# Confidential Information of ARM, Inc.
# Use subject to ARM license.
# Copyright (c) 2026 ARM, Inc.

# ACI Version r0p0-00eac0

# Reifier 3.1.1

VERSION 5.6 ;

BUSBITCHARS "[]" ;

#name: sram_sp_hdc_svt_rvt_hvt Compiler|TSMC cln65gplus 65nm Process, 0.525um2 Bitcell
#version: r0p0-00eac0
#comment: 
#configuration:  -instname "picosoc_sram_2048x32" -words 2048 -bits 32 -frequency 100 -mux 16 -pipeline off -write_mask on -wp_size 8 -write_thru on -top_layer "m5-m9" -power_type otc -redundancy off -rcols 2 -rrows 2 -bmux off -ser none -back_biasing off -power_gating off -retention on -ema on -atf off -cust_comment "" -bus_notation on -left_bus_delim "[" -right_bus_delim "]" -pwr_gnd_rename "VDDPE:VDDPE,VDDCE:VDDCE,VSSE:VSSE" -prefix "" -name_case upper -check_instname off -diodes on -drive 6 -dnw off -asvm on -corners ff_1p10v_1p10v_125c,tt_1p00v_1p00v_25c,ff_1p10v_1p10v_0c,ss_0p90v_0p90v_125c,ff_1p10v_1p10v_m40c,ss_0p90v_0p90v_m40c
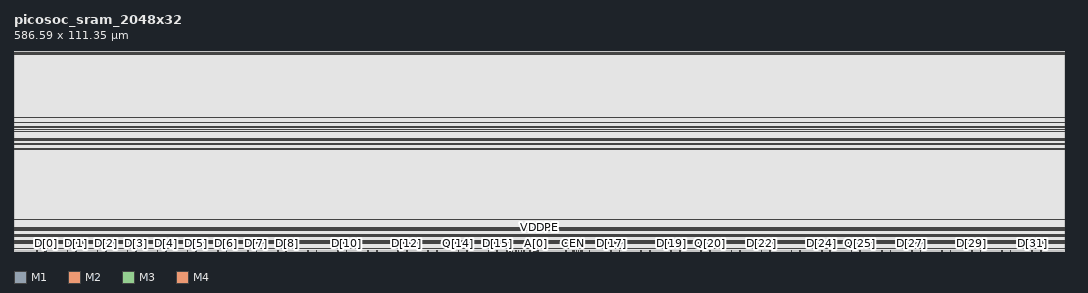
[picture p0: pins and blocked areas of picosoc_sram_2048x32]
MACRO picosoc_sram_2048x32
  FOREIGN picosoc_sram_2048x32 0 0 ;
  SYMMETRY X Y R90 ;
  SIZE 586.59 BY 111.35 ;
  CLASS BLOCK ;
  PIN A[1]
    DIRECTION INPUT ;
    USE SIGNAL ;
    SHAPE ABUTMENT ;
    PORT
      LAYER M1 ;
      RECT 290.67 0.0 291.01 0.2 ;
      LAYER M2 ;
      RECT 290.67 0.0 291.01 0.2 ;
      LAYER M3 ;
      RECT 290.67 0.0 291.01 0.2 ;
      LAYER M4 ;
      RECT 290.67 0.0 291.01 0.34 ;
      END
    ANTENNAGATEAREA 0.009 ;
    ANTENNADIFFAREA 0.1024 ;
    END A[1]
  PIN A[2]
    DIRECTION INPUT ;
    USE SIGNAL ;
    SHAPE ABUTMENT ;
    PORT
      LAYER M4 ;
      RECT 289.945 0.0 290.285 0.34 ;
      LAYER M3 ;
      RECT 289.945 0.0 290.285 0.2 ;
      LAYER M2 ;
      RECT 289.945 0.0 290.285 0.2 ;
      LAYER M1 ;
      RECT 289.945 0.0 290.285 0.2 ;
      END
    ANTENNAGATEAREA 0.009 ;
    ANTENNADIFFAREA 0.1024 ;
    END A[2]
  PIN A[0]
    DIRECTION INPUT ;
    USE SIGNAL ;
    SHAPE ABUTMENT ;
    PORT
      LAYER M1 ;
      RECT 291.345 0.0 291.685 0.2 ;
      LAYER M2 ;
      RECT 291.345 0.0 291.685 0.2 ;
      LAYER M3 ;
      RECT 291.345 0.0 291.685 0.2 ;
      LAYER M4 ;
      RECT 291.345 0.0 291.685 0.34 ;
      END
    ANTENNAGATEAREA 0.009 ;
    ANTENNADIFFAREA 0.1024 ;
    END A[0]
  PIN A[3]
    DIRECTION INPUT ;
    USE SIGNAL ;
    SHAPE ABUTMENT ;
    PORT
      LAYER M4 ;
      RECT 288.12 0.0 288.46 0.34 ;
      LAYER M3 ;
      RECT 288.12 0.0 288.46 0.2 ;
      LAYER M2 ;
      RECT 288.12 0.0 288.46 0.2 ;
      LAYER M1 ;
      RECT 288.12 0.0 288.46 0.2 ;
      END
    ANTENNAGATEAREA 0.009 ;
    ANTENNADIFFAREA 0.1024 ;
    END A[3]
  PIN EMA[0]
    DIRECTION INPUT ;
    USE SIGNAL ;
    SHAPE ABUTMENT ;
    PORT
      LAYER M1 ;
      RECT 292.165 0.0 292.505 0.2 ;
      LAYER M2 ;
      RECT 292.165 0.0 292.505 0.2 ;
      LAYER M3 ;
      RECT 292.165 0.0 292.505 0.2 ;
      LAYER M4 ;
      RECT 292.165 0.0 292.505 0.34 ;
      END
    ANTENNAGATEAREA 0.009 ;
    ANTENNADIFFAREA 0.1024 ;
    END EMA[0]
  PIN A[4]
    DIRECTION INPUT ;
    USE SIGNAL ;
    SHAPE ABUTMENT ;
    PORT
      LAYER M4 ;
      RECT 284.87 0.0 285.21 0.34 ;
      LAYER M3 ;
      RECT 284.87 0.0 285.21 0.2 ;
      LAYER M2 ;
      RECT 284.87 0.0 285.21 0.2 ;
      LAYER M1 ;
      RECT 284.87 0.0 285.21 0.2 ;
      END
    ANTENNAGATEAREA 0.009 ;
    ANTENNADIFFAREA 0.1024 ;
    END A[4]
  PIN EMA[1]
    DIRECTION INPUT ;
    USE SIGNAL ;
    SHAPE ABUTMENT ;
    PORT
      LAYER M1 ;
      RECT 292.745 0.0 293.085 0.2 ;
      LAYER M2 ;
      RECT 292.745 0.0 293.085 0.2 ;
      LAYER M3 ;
      RECT 292.745 0.0 293.085 0.2 ;
      LAYER M4 ;
      RECT 292.745 0.0 293.085 0.34 ;
      END
    ANTENNAGATEAREA 0.009 ;
    ANTENNADIFFAREA 0.1024 ;
    END EMA[1]
  PIN A[5]
    DIRECTION INPUT ;
    USE SIGNAL ;
    SHAPE ABUTMENT ;
    PORT
      LAYER M4 ;
      RECT 283.45 0.0 283.79 0.34 ;
      LAYER M3 ;
      RECT 283.45 0.0 283.79 0.2 ;
      LAYER M2 ;
      RECT 283.45 0.0 283.79 0.2 ;
      LAYER M1 ;
      RECT 283.45 0.0 283.79 0.2 ;
      END
    ANTENNAGATEAREA 0.009 ;
    ANTENNADIFFAREA 0.1024 ;
    END A[5]
  PIN GWEN
    DIRECTION INPUT ;
    USE SIGNAL ;
    SHAPE ABUTMENT ;
    PORT
      LAYER M1 ;
      RECT 308.135 0.0 308.475 0.2 ;
      LAYER M2 ;
      RECT 308.135 0.0 308.475 0.2 ;
      LAYER M3 ;
      RECT 308.135 0.0 308.475 0.2 ;
      LAYER M4 ;
      RECT 308.135 0.0 308.475 0.34 ;
      END
    ANTENNAGATEAREA 0.009 ;
    ANTENNADIFFAREA 0.1024 ;
    END GWEN
  PIN A[6]
    DIRECTION INPUT ;
    USE SIGNAL ;
    SHAPE ABUTMENT ;
    PORT
      LAYER M4 ;
      RECT 281.62 0.0 281.96 0.34 ;
      LAYER M3 ;
      RECT 281.62 0.0 281.96 0.2 ;
      LAYER M2 ;
      RECT 281.62 0.0 281.96 0.2 ;
      LAYER M1 ;
      RECT 281.62 0.0 281.96 0.2 ;
      END
    ANTENNAGATEAREA 0.009 ;
    ANTENNADIFFAREA 0.1024 ;
    END A[6]
  PIN CEN
    DIRECTION INPUT ;
    USE SIGNAL ;
    SHAPE ABUTMENT ;
    PORT
      LAYER M1 ;
      RECT 312.22 0.0 312.56 0.2 ;
      LAYER M2 ;
      RECT 312.22 0.0 312.56 0.2 ;
      LAYER M3 ;
      RECT 312.22 0.0 312.56 0.2 ;
      LAYER M4 ;
      RECT 312.22 0.0 312.56 0.34 ;
      END
    ANTENNAGATEAREA 0.009 ;
    ANTENNADIFFAREA 0.1024 ;
    END CEN
  PIN A[7]
    DIRECTION INPUT ;
    USE SIGNAL ;
    SHAPE ABUTMENT ;
    PORT
      LAYER M4 ;
      RECT 280.2 0.0 280.54 0.34 ;
      LAYER M3 ;
      RECT 280.2 0.0 280.54 0.2 ;
      LAYER M2 ;
      RECT 280.2 0.0 280.54 0.2 ;
      LAYER M1 ;
      RECT 280.2 0.0 280.54 0.2 ;
      END
    ANTENNAGATEAREA 0.009 ;
    ANTENNADIFFAREA 0.1024 ;
    END A[7]
  PIN RETN
    DIRECTION INPUT ;
    USE SIGNAL ;
    SHAPE ABUTMENT ;
    PORT
      LAYER M1 ;
      RECT 313.025 0.0 313.365 0.2 ;
      LAYER M2 ;
      RECT 313.025 0.0 313.365 0.2 ;
      LAYER M3 ;
      RECT 313.025 0.0 313.365 0.2 ;
      LAYER M4 ;
      RECT 313.025 0.0 313.365 0.34 ;
      END
    ANTENNAGATEAREA 0.009 ;
    ANTENNADIFFAREA 0.1024 ;
    END RETN
  PIN A[8]
    DIRECTION INPUT ;
    USE SIGNAL ;
    SHAPE ABUTMENT ;
    PORT
      LAYER M4 ;
      RECT 278.37 0.0 278.71 0.34 ;
      LAYER M3 ;
      RECT 278.37 0.0 278.71 0.2 ;
      LAYER M2 ;
      RECT 278.37 0.0 278.71 0.2 ;
      LAYER M1 ;
      RECT 278.37 0.0 278.71 0.2 ;
      END
    ANTENNAGATEAREA 0.009 ;
    ANTENNADIFFAREA 0.1024 ;
    END A[8]
  PIN EMA[2]
    DIRECTION INPUT ;
    USE SIGNAL ;
    SHAPE ABUTMENT ;
    PORT
      LAYER M1 ;
      RECT 314.08 0.0 314.42 0.2 ;
      LAYER M2 ;
      RECT 314.08 0.0 314.42 0.2 ;
      LAYER M3 ;
      RECT 314.08 0.0 314.42 0.2 ;
      LAYER M4 ;
      RECT 314.08 0.0 314.42 0.34 ;
      END
    ANTENNAGATEAREA 0.009 ;
    ANTENNADIFFAREA 0.1024 ;
    END EMA[2]
  PIN A[9]
    DIRECTION INPUT ;
    USE SIGNAL ;
    SHAPE ABUTMENT ;
    PORT
      LAYER M4 ;
      RECT 276.95 0.0 277.29 0.34 ;
      LAYER M3 ;
      RECT 276.95 0.0 277.29 0.2 ;
      LAYER M2 ;
      RECT 276.95 0.0 277.29 0.2 ;
      LAYER M1 ;
      RECT 276.95 0.0 277.29 0.2 ;
      END
    ANTENNAGATEAREA 0.009 ;
    ANTENNADIFFAREA 0.1024 ;
    END A[9]
  PIN CLK
    DIRECTION INPUT ;
    USE SIGNAL ;
    SHAPE ABUTMENT ;
    PORT
      LAYER M1 ;
      RECT 315.09 0.0 315.43 0.2 ;
      LAYER M2 ;
      RECT 315.09 0.0 315.43 0.2 ;
      LAYER M3 ;
      RECT 315.09 0.0 315.43 0.2 ;
      LAYER M4 ;
      RECT 315.09 0.0 315.43 0.34 ;
      END
    ANTENNAGATEAREA 0.009 ;
    ANTENNADIFFAREA 0.1024 ;
    END CLK
  PIN A[10]
    DIRECTION INPUT ;
    USE SIGNAL ;
    SHAPE ABUTMENT ;
    PORT
      LAYER M4 ;
      RECT 275.12 0.0 275.46 0.34 ;
      LAYER M3 ;
      RECT 275.12 0.0 275.46 0.2 ;
      LAYER M2 ;
      RECT 275.12 0.0 275.46 0.2 ;
      LAYER M1 ;
      RECT 275.12 0.0 275.46 0.2 ;
      END
    ANTENNAGATEAREA 0.009 ;
    ANTENNADIFFAREA 0.1024 ;
    END A[10]
  PIN D[16]
    DIRECTION INPUT ;
    USE SIGNAL ;
    SHAPE ABUTMENT ;
    PORT
      LAYER M1 ;
      RECT 316.575 0.0 316.915 0.2 ;
      LAYER M2 ;
      RECT 316.575 0.0 316.915 0.2 ;
      LAYER M3 ;
      RECT 316.575 0.0 316.915 0.2 ;
      LAYER M4 ;
      RECT 316.575 0.0 316.915 0.34 ;
      END
    ANTENNAGATEAREA 0.009 ;
    ANTENNADIFFAREA 0.1024 ;
    END D[16]
  PIN D[15]
    DIRECTION INPUT ;
    USE SIGNAL ;
    SHAPE ABUTMENT ;
    PORT
      LAYER M4 ;
      RECT 269.675 0.0 270.015 0.34 ;
      LAYER M3 ;
      RECT 269.675 0.0 270.015 0.2 ;
      LAYER M2 ;
      RECT 269.675 0.0 270.015 0.2 ;
      LAYER M1 ;
      RECT 269.675 0.0 270.015 0.2 ;
      END
    ANTENNAGATEAREA 0.009 ;
    ANTENNADIFFAREA 0.1024 ;
    END D[15]
  PIN WEN[2]
    DIRECTION INPUT ;
    USE SIGNAL ;
    SHAPE ABUTMENT ;
    PORT
      LAYER M1 ;
      RECT 317.155 0.0 317.495 0.2 ;
      LAYER M2 ;
      RECT 317.155 0.0 317.495 0.2 ;
      LAYER M3 ;
      RECT 317.155 0.0 317.495 0.2 ;
      LAYER M4 ;
      RECT 317.155 0.0 317.495 0.34 ;
      END
    ANTENNAGATEAREA 0.009 ;
    ANTENNADIFFAREA 0.1024 ;
    END WEN[2]
  PIN Q[15]
    DIRECTION OUTPUT ;
    USE SIGNAL ;
    SHAPE ABUTMENT ;
    PORT
      LAYER M4 ;
      RECT 264.845 0.0 265.185 0.34 ;
      LAYER M3 ;
      RECT 264.845 0.0 265.185 0.2 ;
      LAYER M2 ;
      RECT 264.845 0.0 265.185 0.2 ;
      LAYER M1 ;
      RECT 264.845 0.0 265.185 0.2 ;
      END
    ANTENNADIFFAREA 0.1024 ;
    END Q[15]
  PIN Q[16]
    DIRECTION OUTPUT ;
    USE SIGNAL ;
    SHAPE ABUTMENT ;
    PORT
      LAYER M1 ;
      RECT 321.405 0.0 321.745 0.2 ;
      LAYER M2 ;
      RECT 321.405 0.0 321.745 0.2 ;
      LAYER M3 ;
      RECT 321.405 0.0 321.745 0.2 ;
      LAYER M4 ;
      RECT 321.405 0.0 321.745 0.34 ;
      END
    ANTENNADIFFAREA 0.1024 ;
    END Q[16]
  PIN D[14]
    DIRECTION INPUT ;
    USE SIGNAL ;
    SHAPE ABUTMENT ;
    PORT
      LAYER M4 ;
      RECT 252.875 0.0 253.215 0.34 ;
      LAYER M3 ;
      RECT 252.875 0.0 253.215 0.2 ;
      LAYER M2 ;
      RECT 252.875 0.0 253.215 0.2 ;
      LAYER M1 ;
      RECT 252.875 0.0 253.215 0.2 ;
      END
    ANTENNAGATEAREA 0.009 ;
    ANTENNADIFFAREA 0.1024 ;
    END D[14]
  PIN D[17]
    DIRECTION INPUT ;
    USE SIGNAL ;
    SHAPE ABUTMENT ;
    PORT
      LAYER M1 ;
      RECT 333.375 0.0 333.715 0.2 ;
      LAYER M2 ;
      RECT 333.375 0.0 333.715 0.2 ;
      LAYER M3 ;
      RECT 333.375 0.0 333.715 0.2 ;
      LAYER M4 ;
      RECT 333.375 0.0 333.715 0.34 ;
      END
    ANTENNAGATEAREA 0.009 ;
    ANTENNADIFFAREA 0.1024 ;
    END D[17]
  PIN Q[14]
    DIRECTION OUTPUT ;
    USE SIGNAL ;
    SHAPE ABUTMENT ;
    PORT
      LAYER M4 ;
      RECT 248.045 0.0 248.385 0.34 ;
      LAYER M3 ;
      RECT 248.045 0.0 248.385 0.2 ;
      LAYER M2 ;
      RECT 248.045 0.0 248.385 0.2 ;
      LAYER M1 ;
      RECT 248.045 0.0 248.385 0.2 ;
      END
    ANTENNADIFFAREA 0.1024 ;
    END Q[14]
  PIN Q[17]
    DIRECTION OUTPUT ;
    USE SIGNAL ;
    SHAPE ABUTMENT ;
    PORT
      LAYER M1 ;
      RECT 338.205 0.0 338.545 0.2 ;
      LAYER M2 ;
      RECT 338.205 0.0 338.545 0.2 ;
      LAYER M3 ;
      RECT 338.205 0.0 338.545 0.2 ;
      LAYER M4 ;
      RECT 338.205 0.0 338.545 0.34 ;
      END
    ANTENNADIFFAREA 0.1024 ;
    END Q[17]
  PIN D[13]
    DIRECTION INPUT ;
    USE SIGNAL ;
    SHAPE ABUTMENT ;
    PORT
      LAYER M4 ;
      RECT 236.075 0.0 236.415 0.34 ;
      LAYER M3 ;
      RECT 236.075 0.0 236.415 0.2 ;
      LAYER M2 ;
      RECT 236.075 0.0 236.415 0.2 ;
      LAYER M1 ;
      RECT 236.075 0.0 236.415 0.2 ;
      END
    ANTENNAGATEAREA 0.009 ;
    ANTENNADIFFAREA 0.1024 ;
    END D[13]
  PIN D[18]
    DIRECTION INPUT ;
    USE SIGNAL ;
    SHAPE ABUTMENT ;
    PORT
      LAYER M1 ;
      RECT 350.175 0.0 350.515 0.2 ;
      LAYER M2 ;
      RECT 350.175 0.0 350.515 0.2 ;
      LAYER M3 ;
      RECT 350.175 0.0 350.515 0.2 ;
      LAYER M4 ;
      RECT 350.175 0.0 350.515 0.34 ;
      END
    ANTENNAGATEAREA 0.009 ;
    ANTENNADIFFAREA 0.1024 ;
    END D[18]
  PIN Q[13]
    DIRECTION OUTPUT ;
    USE SIGNAL ;
    SHAPE ABUTMENT ;
    PORT
      LAYER M4 ;
      RECT 231.245 0.0 231.585 0.34 ;
      LAYER M3 ;
      RECT 231.245 0.0 231.585 0.2 ;
      LAYER M2 ;
      RECT 231.245 0.0 231.585 0.2 ;
      LAYER M1 ;
      RECT 231.245 0.0 231.585 0.2 ;
      END
    ANTENNADIFFAREA 0.1024 ;
    END Q[13]
  PIN Q[18]
    DIRECTION OUTPUT ;
    USE SIGNAL ;
    SHAPE ABUTMENT ;
    PORT
      LAYER M1 ;
      RECT 355.005 0.0 355.345 0.2 ;
      LAYER M2 ;
      RECT 355.005 0.0 355.345 0.2 ;
      LAYER M3 ;
      RECT 355.005 0.0 355.345 0.2 ;
      LAYER M4 ;
      RECT 355.005 0.0 355.345 0.34 ;
      END
    ANTENNADIFFAREA 0.1024 ;
    END Q[18]
  PIN D[12]
    DIRECTION INPUT ;
    USE SIGNAL ;
    SHAPE ABUTMENT ;
    PORT
      LAYER M4 ;
      RECT 219.275 0.0 219.615 0.34 ;
      LAYER M3 ;
      RECT 219.275 0.0 219.615 0.2 ;
      LAYER M2 ;
      RECT 219.275 0.0 219.615 0.2 ;
      LAYER M1 ;
      RECT 219.275 0.0 219.615 0.2 ;
      END
    ANTENNAGATEAREA 0.009 ;
    ANTENNADIFFAREA 0.1024 ;
    END D[12]
  PIN D[19]
    DIRECTION INPUT ;
    USE SIGNAL ;
    SHAPE ABUTMENT ;
    PORT
      LAYER M1 ;
      RECT 366.975 0.0 367.315 0.2 ;
      LAYER M2 ;
      RECT 366.975 0.0 367.315 0.2 ;
      LAYER M3 ;
      RECT 366.975 0.0 367.315 0.2 ;
      LAYER M4 ;
      RECT 366.975 0.0 367.315 0.34 ;
      END
    ANTENNAGATEAREA 0.009 ;
    ANTENNADIFFAREA 0.1024 ;
    END D[19]
  PIN Q[12]
    DIRECTION OUTPUT ;
    USE SIGNAL ;
    SHAPE ABUTMENT ;
    PORT
      LAYER M4 ;
      RECT 214.445 0.0 214.785 0.34 ;
      LAYER M3 ;
      RECT 214.445 0.0 214.785 0.2 ;
      LAYER M2 ;
      RECT 214.445 0.0 214.785 0.2 ;
      LAYER M1 ;
      RECT 214.445 0.0 214.785 0.2 ;
      END
    ANTENNADIFFAREA 0.1024 ;
    END Q[12]
  PIN Q[19]
    DIRECTION OUTPUT ;
    USE SIGNAL ;
    SHAPE ABUTMENT ;
    PORT
      LAYER M1 ;
      RECT 371.805 0.0 372.145 0.2 ;
      LAYER M2 ;
      RECT 371.805 0.0 372.145 0.2 ;
      LAYER M3 ;
      RECT 371.805 0.0 372.145 0.2 ;
      LAYER M4 ;
      RECT 371.805 0.0 372.145 0.34 ;
      END
    ANTENNADIFFAREA 0.1024 ;
    END Q[19]
  PIN D[11]
    DIRECTION INPUT ;
    USE SIGNAL ;
    SHAPE ABUTMENT ;
    PORT
      LAYER M4 ;
      RECT 202.475 0.0 202.815 0.34 ;
      LAYER M3 ;
      RECT 202.475 0.0 202.815 0.2 ;
      LAYER M2 ;
      RECT 202.475 0.0 202.815 0.2 ;
      LAYER M1 ;
      RECT 202.475 0.0 202.815 0.2 ;
      END
    ANTENNAGATEAREA 0.009 ;
    ANTENNADIFFAREA 0.1024 ;
    END D[11]
  PIN D[20]
    DIRECTION INPUT ;
    USE SIGNAL ;
    SHAPE ABUTMENT ;
    PORT
      LAYER M1 ;
      RECT 383.775 0.0 384.115 0.2 ;
      LAYER M2 ;
      RECT 383.775 0.0 384.115 0.2 ;
      LAYER M3 ;
      RECT 383.775 0.0 384.115 0.2 ;
      LAYER M4 ;
      RECT 383.775 0.0 384.115 0.34 ;
      END
    ANTENNAGATEAREA 0.009 ;
    ANTENNADIFFAREA 0.1024 ;
    END D[20]
  PIN Q[11]
    DIRECTION OUTPUT ;
    USE SIGNAL ;
    SHAPE ABUTMENT ;
    PORT
      LAYER M4 ;
      RECT 197.645 0.0 197.985 0.34 ;
      LAYER M3 ;
      RECT 197.645 0.0 197.985 0.2 ;
      LAYER M2 ;
      RECT 197.645 0.0 197.985 0.2 ;
      LAYER M1 ;
      RECT 197.645 0.0 197.985 0.2 ;
      END
    ANTENNADIFFAREA 0.1024 ;
    END Q[11]
  PIN Q[20]
    DIRECTION OUTPUT ;
    USE SIGNAL ;
    SHAPE ABUTMENT ;
    PORT
      LAYER M1 ;
      RECT 388.605 0.0 388.945 0.2 ;
      LAYER M2 ;
      RECT 388.605 0.0 388.945 0.2 ;
      LAYER M3 ;
      RECT 388.605 0.0 388.945 0.2 ;
      LAYER M4 ;
      RECT 388.605 0.0 388.945 0.34 ;
      END
    ANTENNADIFFAREA 0.1024 ;
    END Q[20]
  PIN D[10]
    DIRECTION INPUT ;
    USE SIGNAL ;
    SHAPE ABUTMENT ;
    PORT
      LAYER M4 ;
      RECT 185.675 0.0 186.015 0.34 ;
      LAYER M3 ;
      RECT 185.675 0.0 186.015 0.2 ;
      LAYER M2 ;
      RECT 185.675 0.0 186.015 0.2 ;
      LAYER M1 ;
      RECT 185.675 0.0 186.015 0.2 ;
      END
    ANTENNAGATEAREA 0.009 ;
    ANTENNADIFFAREA 0.1024 ;
    END D[10]
  PIN D[21]
    DIRECTION INPUT ;
    USE SIGNAL ;
    SHAPE ABUTMENT ;
    PORT
      LAYER M1 ;
      RECT 400.575 0.0 400.915 0.2 ;
      LAYER M2 ;
      RECT 400.575 0.0 400.915 0.2 ;
      LAYER M3 ;
      RECT 400.575 0.0 400.915 0.2 ;
      LAYER M4 ;
      RECT 400.575 0.0 400.915 0.34 ;
      END
    ANTENNAGATEAREA 0.009 ;
    ANTENNADIFFAREA 0.1024 ;
    END D[21]
  PIN Q[10]
    DIRECTION OUTPUT ;
    USE SIGNAL ;
    SHAPE ABUTMENT ;
    PORT
      LAYER M4 ;
      RECT 180.845 0.0 181.185 0.34 ;
      LAYER M3 ;
      RECT 180.845 0.0 181.185 0.2 ;
      LAYER M2 ;
      RECT 180.845 0.0 181.185 0.2 ;
      LAYER M1 ;
      RECT 180.845 0.0 181.185 0.2 ;
      END
    ANTENNADIFFAREA 0.1024 ;
    END Q[10]
  PIN Q[21]
    DIRECTION OUTPUT ;
    USE SIGNAL ;
    SHAPE ABUTMENT ;
    PORT
      LAYER M1 ;
      RECT 405.405 0.0 405.745 0.2 ;
      LAYER M2 ;
      RECT 405.405 0.0 405.745 0.2 ;
      LAYER M3 ;
      RECT 405.405 0.0 405.745 0.2 ;
      LAYER M4 ;
      RECT 405.405 0.0 405.745 0.34 ;
      END
    ANTENNADIFFAREA 0.1024 ;
    END Q[21]
  PIN D[9]
    DIRECTION INPUT ;
    USE SIGNAL ;
    SHAPE ABUTMENT ;
    PORT
      LAYER M4 ;
      RECT 168.875 0.0 169.215 0.34 ;
      LAYER M3 ;
      RECT 168.875 0.0 169.215 0.2 ;
      LAYER M2 ;
      RECT 168.875 0.0 169.215 0.2 ;
      LAYER M1 ;
      RECT 168.875 0.0 169.215 0.2 ;
      END
    ANTENNAGATEAREA 0.009 ;
    ANTENNADIFFAREA 0.1024 ;
    END D[9]
  PIN D[22]
    DIRECTION INPUT ;
    USE SIGNAL ;
    SHAPE ABUTMENT ;
    PORT
      LAYER M1 ;
      RECT 417.375 0.0 417.715 0.2 ;
      LAYER M2 ;
      RECT 417.375 0.0 417.715 0.2 ;
      LAYER M3 ;
      RECT 417.375 0.0 417.715 0.2 ;
      LAYER M4 ;
      RECT 417.375 0.0 417.715 0.34 ;
      END
    ANTENNAGATEAREA 0.009 ;
    ANTENNADIFFAREA 0.1024 ;
    END D[22]
  PIN Q[9]
    DIRECTION OUTPUT ;
    USE SIGNAL ;
    SHAPE ABUTMENT ;
    PORT
      LAYER M4 ;
      RECT 164.045 0.0 164.385 0.34 ;
      LAYER M3 ;
      RECT 164.045 0.0 164.385 0.2 ;
      LAYER M2 ;
      RECT 164.045 0.0 164.385 0.2 ;
      LAYER M1 ;
      RECT 164.045 0.0 164.385 0.2 ;
      END
    ANTENNADIFFAREA 0.1024 ;
    END Q[9]
  PIN Q[22]
    DIRECTION OUTPUT ;
    USE SIGNAL ;
    SHAPE ABUTMENT ;
    PORT
      LAYER M1 ;
      RECT 422.205 0.0 422.545 0.2 ;
      LAYER M2 ;
      RECT 422.205 0.0 422.545 0.2 ;
      LAYER M3 ;
      RECT 422.205 0.0 422.545 0.2 ;
      LAYER M4 ;
      RECT 422.205 0.0 422.545 0.34 ;
      END
    ANTENNADIFFAREA 0.1024 ;
    END Q[22]
  PIN D[8]
    DIRECTION INPUT ;
    USE SIGNAL ;
    SHAPE ABUTMENT ;
    PORT
      LAYER M4 ;
      RECT 152.075 0.0 152.415 0.34 ;
      LAYER M3 ;
      RECT 152.075 0.0 152.415 0.2 ;
      LAYER M2 ;
      RECT 152.075 0.0 152.415 0.2 ;
      LAYER M1 ;
      RECT 152.075 0.0 152.415 0.2 ;
      END
    ANTENNAGATEAREA 0.009 ;
    ANTENNADIFFAREA 0.1024 ;
    END D[8]
  PIN D[23]
    DIRECTION INPUT ;
    USE SIGNAL ;
    SHAPE ABUTMENT ;
    PORT
      LAYER M1 ;
      RECT 434.175 0.0 434.515 0.2 ;
      LAYER M2 ;
      RECT 434.175 0.0 434.515 0.2 ;
      LAYER M3 ;
      RECT 434.175 0.0 434.515 0.2 ;
      LAYER M4 ;
      RECT 434.175 0.0 434.515 0.34 ;
      END
    ANTENNAGATEAREA 0.009 ;
    ANTENNADIFFAREA 0.1024 ;
    END D[23]
  PIN WEN[1]
    DIRECTION INPUT ;
    USE SIGNAL ;
    SHAPE ABUTMENT ;
    PORT
      LAYER M4 ;
      RECT 151.495 0.0 151.835 0.34 ;
      LAYER M3 ;
      RECT 151.495 0.0 151.835 0.2 ;
      LAYER M2 ;
      RECT 151.495 0.0 151.835 0.2 ;
      LAYER M1 ;
      RECT 151.495 0.0 151.835 0.2 ;
      END
    ANTENNAGATEAREA 0.009 ;
    ANTENNADIFFAREA 0.1024 ;
    END WEN[1]
  PIN Q[23]
    DIRECTION OUTPUT ;
    USE SIGNAL ;
    SHAPE ABUTMENT ;
    PORT
      LAYER M1 ;
      RECT 439.005 0.0 439.345 0.2 ;
      LAYER M2 ;
      RECT 439.005 0.0 439.345 0.2 ;
      LAYER M3 ;
      RECT 439.005 0.0 439.345 0.2 ;
      LAYER M4 ;
      RECT 439.005 0.0 439.345 0.34 ;
      END
    ANTENNADIFFAREA 0.1024 ;
    END Q[23]
  PIN Q[8]
    DIRECTION OUTPUT ;
    USE SIGNAL ;
    SHAPE ABUTMENT ;
    PORT
      LAYER M4 ;
      RECT 147.245 0.0 147.585 0.34 ;
      LAYER M3 ;
      RECT 147.245 0.0 147.585 0.2 ;
      LAYER M2 ;
      RECT 147.245 0.0 147.585 0.2 ;
      LAYER M1 ;
      RECT 147.245 0.0 147.585 0.2 ;
      END
    ANTENNADIFFAREA 0.1024 ;
    END Q[8]
  PIN D[24]
    DIRECTION INPUT ;
    USE SIGNAL ;
    SHAPE ABUTMENT ;
    PORT
      LAYER M1 ;
      RECT 450.975 0.0 451.315 0.2 ;
      LAYER M2 ;
      RECT 450.975 0.0 451.315 0.2 ;
      LAYER M3 ;
      RECT 450.975 0.0 451.315 0.2 ;
      LAYER M4 ;
      RECT 450.975 0.0 451.315 0.34 ;
      END
    ANTENNAGATEAREA 0.009 ;
    ANTENNADIFFAREA 0.1024 ;
    END D[24]
  PIN D[7]
    DIRECTION INPUT ;
    USE SIGNAL ;
    SHAPE ABUTMENT ;
    PORT
      LAYER M4 ;
      RECT 135.275 0.0 135.615 0.34 ;
      LAYER M3 ;
      RECT 135.275 0.0 135.615 0.2 ;
      LAYER M2 ;
      RECT 135.275 0.0 135.615 0.2 ;
      LAYER M1 ;
      RECT 135.275 0.0 135.615 0.2 ;
      END
    ANTENNAGATEAREA 0.009 ;
    ANTENNADIFFAREA 0.1024 ;
    END D[7]
  PIN WEN[3]
    DIRECTION INPUT ;
    USE SIGNAL ;
    SHAPE ABUTMENT ;
    PORT
      LAYER M1 ;
      RECT 451.555 0.0 451.895 0.2 ;
      LAYER M2 ;
      RECT 451.555 0.0 451.895 0.2 ;
      LAYER M3 ;
      RECT 451.555 0.0 451.895 0.2 ;
      LAYER M4 ;
      RECT 451.555 0.0 451.895 0.34 ;
      END
    ANTENNAGATEAREA 0.009 ;
    ANTENNADIFFAREA 0.1024 ;
    END WEN[3]
  PIN Q[7]
    DIRECTION OUTPUT ;
    USE SIGNAL ;
    SHAPE ABUTMENT ;
    PORT
      LAYER M4 ;
      RECT 130.445 0.0 130.785 0.34 ;
      LAYER M3 ;
      RECT 130.445 0.0 130.785 0.2 ;
      LAYER M2 ;
      RECT 130.445 0.0 130.785 0.2 ;
      LAYER M1 ;
      RECT 130.445 0.0 130.785 0.2 ;
      END
    ANTENNADIFFAREA 0.1024 ;
    END Q[7]
  PIN Q[24]
    DIRECTION OUTPUT ;
    USE SIGNAL ;
    SHAPE ABUTMENT ;
    PORT
      LAYER M1 ;
      RECT 455.805 0.0 456.145 0.2 ;
      LAYER M2 ;
      RECT 455.805 0.0 456.145 0.2 ;
      LAYER M3 ;
      RECT 455.805 0.0 456.145 0.2 ;
      LAYER M4 ;
      RECT 455.805 0.0 456.145 0.34 ;
      END
    ANTENNADIFFAREA 0.1024 ;
    END Q[24]
  PIN D[6]
    DIRECTION INPUT ;
    USE SIGNAL ;
    SHAPE ABUTMENT ;
    PORT
      LAYER M4 ;
      RECT 118.475 0.0 118.815 0.34 ;
      LAYER M3 ;
      RECT 118.475 0.0 118.815 0.2 ;
      LAYER M2 ;
      RECT 118.475 0.0 118.815 0.2 ;
      LAYER M1 ;
      RECT 118.475 0.0 118.815 0.2 ;
      END
    ANTENNAGATEAREA 0.009 ;
    ANTENNADIFFAREA 0.1024 ;
    END D[6]
  PIN D[25]
    DIRECTION INPUT ;
    USE SIGNAL ;
    SHAPE ABUTMENT ;
    PORT
      LAYER M1 ;
      RECT 467.775 0.0 468.115 0.2 ;
      LAYER M2 ;
      RECT 467.775 0.0 468.115 0.2 ;
      LAYER M3 ;
      RECT 467.775 0.0 468.115 0.2 ;
      LAYER M4 ;
      RECT 467.775 0.0 468.115 0.34 ;
      END
    ANTENNAGATEAREA 0.009 ;
    ANTENNADIFFAREA 0.1024 ;
    END D[25]
  PIN Q[6]
    DIRECTION OUTPUT ;
    USE SIGNAL ;
    SHAPE ABUTMENT ;
    PORT
      LAYER M4 ;
      RECT 113.645 0.0 113.985 0.34 ;
      LAYER M3 ;
      RECT 113.645 0.0 113.985 0.2 ;
      LAYER M2 ;
      RECT 113.645 0.0 113.985 0.2 ;
      LAYER M1 ;
      RECT 113.645 0.0 113.985 0.2 ;
      END
    ANTENNADIFFAREA 0.1024 ;
    END Q[6]
  PIN Q[25]
    DIRECTION OUTPUT ;
    USE SIGNAL ;
    SHAPE ABUTMENT ;
    PORT
      LAYER M1 ;
      RECT 472.605 0.0 472.945 0.2 ;
      LAYER M2 ;
      RECT 472.605 0.0 472.945 0.2 ;
      LAYER M3 ;
      RECT 472.605 0.0 472.945 0.2 ;
      LAYER M4 ;
      RECT 472.605 0.0 472.945 0.34 ;
      END
    ANTENNADIFFAREA 0.1024 ;
    END Q[25]
  PIN D[5]
    DIRECTION INPUT ;
    USE SIGNAL ;
    SHAPE ABUTMENT ;
    PORT
      LAYER M4 ;
      RECT 101.675 0.0 102.015 0.34 ;
      LAYER M3 ;
      RECT 101.675 0.0 102.015 0.2 ;
      LAYER M2 ;
      RECT 101.675 0.0 102.015 0.2 ;
      LAYER M1 ;
      RECT 101.675 0.0 102.015 0.2 ;
      END
    ANTENNAGATEAREA 0.009 ;
    ANTENNADIFFAREA 0.1024 ;
    END D[5]
  PIN D[26]
    DIRECTION INPUT ;
    USE SIGNAL ;
    SHAPE ABUTMENT ;
    PORT
      LAYER M1 ;
      RECT 484.575 0.0 484.915 0.2 ;
      LAYER M2 ;
      RECT 484.575 0.0 484.915 0.2 ;
      LAYER M3 ;
      RECT 484.575 0.0 484.915 0.2 ;
      LAYER M4 ;
      RECT 484.575 0.0 484.915 0.34 ;
      END
    ANTENNAGATEAREA 0.009 ;
    ANTENNADIFFAREA 0.1024 ;
    END D[26]
  PIN Q[5]
    DIRECTION OUTPUT ;
    USE SIGNAL ;
    SHAPE ABUTMENT ;
    PORT
      LAYER M4 ;
      RECT 96.845 0.0 97.185 0.34 ;
      LAYER M3 ;
      RECT 96.845 0.0 97.185 0.2 ;
      LAYER M2 ;
      RECT 96.845 0.0 97.185 0.2 ;
      LAYER M1 ;
      RECT 96.845 0.0 97.185 0.2 ;
      END
    ANTENNADIFFAREA 0.1024 ;
    END Q[5]
  PIN Q[26]
    DIRECTION OUTPUT ;
    USE SIGNAL ;
    SHAPE ABUTMENT ;
    PORT
      LAYER M1 ;
      RECT 489.405 0.0 489.745 0.2 ;
      LAYER M2 ;
      RECT 489.405 0.0 489.745 0.2 ;
      LAYER M3 ;
      RECT 489.405 0.0 489.745 0.2 ;
      LAYER M4 ;
      RECT 489.405 0.0 489.745 0.34 ;
      END
    ANTENNADIFFAREA 0.1024 ;
    END Q[26]
  PIN D[4]
    DIRECTION INPUT ;
    USE SIGNAL ;
    SHAPE ABUTMENT ;
    PORT
      LAYER M4 ;
      RECT 84.875 0.0 85.215 0.34 ;
      LAYER M3 ;
      RECT 84.875 0.0 85.215 0.2 ;
      LAYER M2 ;
      RECT 84.875 0.0 85.215 0.2 ;
      LAYER M1 ;
      RECT 84.875 0.0 85.215 0.2 ;
      END
    ANTENNAGATEAREA 0.009 ;
    ANTENNADIFFAREA 0.1024 ;
    END D[4]
  PIN D[27]
    DIRECTION INPUT ;
    USE SIGNAL ;
    SHAPE ABUTMENT ;
    PORT
      LAYER M1 ;
      RECT 501.375 0.0 501.715 0.2 ;
      LAYER M2 ;
      RECT 501.375 0.0 501.715 0.2 ;
      LAYER M3 ;
      RECT 501.375 0.0 501.715 0.2 ;
      LAYER M4 ;
      RECT 501.375 0.0 501.715 0.34 ;
      END
    ANTENNAGATEAREA 0.009 ;
    ANTENNADIFFAREA 0.1024 ;
    END D[27]
  PIN Q[4]
    DIRECTION OUTPUT ;
    USE SIGNAL ;
    SHAPE ABUTMENT ;
    PORT
      LAYER M4 ;
      RECT 80.045 0.0 80.385 0.34 ;
      LAYER M3 ;
      RECT 80.045 0.0 80.385 0.2 ;
      LAYER M2 ;
      RECT 80.045 0.0 80.385 0.2 ;
      LAYER M1 ;
      RECT 80.045 0.0 80.385 0.2 ;
      END
    ANTENNADIFFAREA 0.1024 ;
    END Q[4]
  PIN Q[27]
    DIRECTION OUTPUT ;
    USE SIGNAL ;
    SHAPE ABUTMENT ;
    PORT
      LAYER M1 ;
      RECT 506.205 0.0 506.545 0.2 ;
      LAYER M2 ;
      RECT 506.205 0.0 506.545 0.2 ;
      LAYER M3 ;
      RECT 506.205 0.0 506.545 0.2 ;
      LAYER M4 ;
      RECT 506.205 0.0 506.545 0.34 ;
      END
    ANTENNADIFFAREA 0.1024 ;
    END Q[27]
  PIN D[3]
    DIRECTION INPUT ;
    USE SIGNAL ;
    SHAPE ABUTMENT ;
    PORT
      LAYER M4 ;
      RECT 68.075 0.0 68.415 0.34 ;
      LAYER M3 ;
      RECT 68.075 0.0 68.415 0.2 ;
      LAYER M2 ;
      RECT 68.075 0.0 68.415 0.2 ;
      LAYER M1 ;
      RECT 68.075 0.0 68.415 0.2 ;
      END
    ANTENNAGATEAREA 0.009 ;
    ANTENNADIFFAREA 0.1024 ;
    END D[3]
  PIN D[28]
    DIRECTION INPUT ;
    USE SIGNAL ;
    SHAPE ABUTMENT ;
    PORT
      LAYER M1 ;
      RECT 518.175 0.0 518.515 0.2 ;
      LAYER M2 ;
      RECT 518.175 0.0 518.515 0.2 ;
      LAYER M3 ;
      RECT 518.175 0.0 518.515 0.2 ;
      LAYER M4 ;
      RECT 518.175 0.0 518.515 0.34 ;
      END
    ANTENNAGATEAREA 0.009 ;
    ANTENNADIFFAREA 0.1024 ;
    END D[28]
  PIN Q[3]
    DIRECTION OUTPUT ;
    USE SIGNAL ;
    SHAPE ABUTMENT ;
    PORT
      LAYER M4 ;
      RECT 63.245 0.0 63.585 0.34 ;
      LAYER M3 ;
      RECT 63.245 0.0 63.585 0.2 ;
      LAYER M2 ;
      RECT 63.245 0.0 63.585 0.2 ;
      LAYER M1 ;
      RECT 63.245 0.0 63.585 0.2 ;
      END
    ANTENNADIFFAREA 0.1024 ;
    END Q[3]
  PIN Q[28]
    DIRECTION OUTPUT ;
    USE SIGNAL ;
    SHAPE ABUTMENT ;
    PORT
      LAYER M1 ;
      RECT 523.005 0.0 523.345 0.2 ;
      LAYER M2 ;
      RECT 523.005 0.0 523.345 0.2 ;
      LAYER M3 ;
      RECT 523.005 0.0 523.345 0.2 ;
      LAYER M4 ;
      RECT 523.005 0.0 523.345 0.34 ;
      END
    ANTENNADIFFAREA 0.1024 ;
    END Q[28]
  PIN D[2]
    DIRECTION INPUT ;
    USE SIGNAL ;
    SHAPE ABUTMENT ;
    PORT
      LAYER M4 ;
      RECT 51.275 0.0 51.615 0.34 ;
      LAYER M3 ;
      RECT 51.275 0.0 51.615 0.2 ;
      LAYER M2 ;
      RECT 51.275 0.0 51.615 0.2 ;
      LAYER M1 ;
      RECT 51.275 0.0 51.615 0.2 ;
      END
    ANTENNAGATEAREA 0.009 ;
    ANTENNADIFFAREA 0.1024 ;
    END D[2]
  PIN D[29]
    DIRECTION INPUT ;
    USE SIGNAL ;
    SHAPE ABUTMENT ;
    PORT
      LAYER M1 ;
      RECT 534.975 0.0 535.315 0.2 ;
      LAYER M2 ;
      RECT 534.975 0.0 535.315 0.2 ;
      LAYER M3 ;
      RECT 534.975 0.0 535.315 0.2 ;
      LAYER M4 ;
      RECT 534.975 0.0 535.315 0.34 ;
      END
    ANTENNAGATEAREA 0.009 ;
    ANTENNADIFFAREA 0.1024 ;
    END D[29]
  PIN Q[2]
    DIRECTION OUTPUT ;
    USE SIGNAL ;
    SHAPE ABUTMENT ;
    PORT
      LAYER M4 ;
      RECT 46.445 0.0 46.785 0.34 ;
      LAYER M3 ;
      RECT 46.445 0.0 46.785 0.2 ;
      LAYER M2 ;
      RECT 46.445 0.0 46.785 0.2 ;
      LAYER M1 ;
      RECT 46.445 0.0 46.785 0.2 ;
      END
    ANTENNADIFFAREA 0.1024 ;
    END Q[2]
  PIN Q[29]
    DIRECTION OUTPUT ;
    USE SIGNAL ;
    SHAPE ABUTMENT ;
    PORT
      LAYER M1 ;
      RECT 539.805 0.0 540.145 0.2 ;
      LAYER M2 ;
      RECT 539.805 0.0 540.145 0.2 ;
      LAYER M3 ;
      RECT 539.805 0.0 540.145 0.2 ;
      LAYER M4 ;
      RECT 539.805 0.0 540.145 0.34 ;
      END
    ANTENNADIFFAREA 0.1024 ;
    END Q[29]
  PIN D[1]
    DIRECTION INPUT ;
    USE SIGNAL ;
    SHAPE ABUTMENT ;
    PORT
      LAYER M4 ;
      RECT 34.475 0.0 34.815 0.34 ;
      LAYER M3 ;
      RECT 34.475 0.0 34.815 0.2 ;
      LAYER M2 ;
      RECT 34.475 0.0 34.815 0.2 ;
      LAYER M1 ;
      RECT 34.475 0.0 34.815 0.2 ;
      END
    ANTENNAGATEAREA 0.009 ;
    ANTENNADIFFAREA 0.1024 ;
    END D[1]
  PIN D[30]
    DIRECTION INPUT ;
    USE SIGNAL ;
    SHAPE ABUTMENT ;
    PORT
      LAYER M1 ;
      RECT 551.775 0.0 552.115 0.2 ;
      LAYER M2 ;
      RECT 551.775 0.0 552.115 0.2 ;
      LAYER M3 ;
      RECT 551.775 0.0 552.115 0.2 ;
      LAYER M4 ;
      RECT 551.775 0.0 552.115 0.34 ;
      END
    ANTENNAGATEAREA 0.009 ;
    ANTENNADIFFAREA 0.1024 ;
    END D[30]
  PIN Q[1]
    DIRECTION OUTPUT ;
    USE SIGNAL ;
    SHAPE ABUTMENT ;
    PORT
      LAYER M4 ;
      RECT 29.645 0.0 29.985 0.34 ;
      LAYER M3 ;
      RECT 29.645 0.0 29.985 0.2 ;
      LAYER M2 ;
      RECT 29.645 0.0 29.985 0.2 ;
      LAYER M1 ;
      RECT 29.645 0.0 29.985 0.2 ;
      END
    ANTENNADIFFAREA 0.1024 ;
    END Q[1]
  PIN Q[30]
    DIRECTION OUTPUT ;
    USE SIGNAL ;
    SHAPE ABUTMENT ;
    PORT
      LAYER M1 ;
      RECT 556.605 0.0 556.945 0.2 ;
      LAYER M2 ;
      RECT 556.605 0.0 556.945 0.2 ;
      LAYER M3 ;
      RECT 556.605 0.0 556.945 0.2 ;
      LAYER M4 ;
      RECT 556.605 0.0 556.945 0.34 ;
      END
    ANTENNADIFFAREA 0.1024 ;
    END Q[30]
  PIN D[0]
    DIRECTION INPUT ;
    USE SIGNAL ;
    SHAPE ABUTMENT ;
    PORT
      LAYER M4 ;
      RECT 17.675 0.0 18.015 0.34 ;
      LAYER M3 ;
      RECT 17.675 0.0 18.015 0.2 ;
      LAYER M2 ;
      RECT 17.675 0.0 18.015 0.2 ;
      LAYER M1 ;
      RECT 17.675 0.0 18.015 0.2 ;
      END
    ANTENNAGATEAREA 0.009 ;
    ANTENNADIFFAREA 0.1024 ;
    END D[0]
  PIN D[31]
    DIRECTION INPUT ;
    USE SIGNAL ;
    SHAPE ABUTMENT ;
    PORT
      LAYER M1 ;
      RECT 568.575 0.0 568.915 0.2 ;
      LAYER M2 ;
      RECT 568.575 0.0 568.915 0.2 ;
      LAYER M3 ;
      RECT 568.575 0.0 568.915 0.2 ;
      LAYER M4 ;
      RECT 568.575 0.0 568.915 0.34 ;
      END
    ANTENNAGATEAREA 0.009 ;
    ANTENNADIFFAREA 0.1024 ;
    END D[31]
  PIN WEN[0]
    DIRECTION INPUT ;
    USE SIGNAL ;
    SHAPE ABUTMENT ;
    PORT
      LAYER M4 ;
      RECT 17.095 0.0 17.435 0.34 ;
      LAYER M3 ;
      RECT 17.095 0.0 17.435 0.2 ;
      LAYER M2 ;
      RECT 17.095 0.0 17.435 0.2 ;
      LAYER M1 ;
      RECT 17.095 0.0 17.435 0.2 ;
      END
    ANTENNAGATEAREA 0.009 ;
    ANTENNADIFFAREA 0.1024 ;
    END WEN[0]
  PIN Q[31]
    DIRECTION OUTPUT ;
    USE SIGNAL ;
    SHAPE ABUTMENT ;
    PORT
      LAYER M1 ;
      RECT 573.405 0.0 573.745 0.2 ;
      LAYER M2 ;
      RECT 573.405 0.0 573.745 0.2 ;
      LAYER M3 ;
      RECT 573.405 0.0 573.745 0.2 ;
      LAYER M4 ;
      RECT 573.405 0.0 573.745 0.34 ;
      END
    ANTENNADIFFAREA 0.1024 ;
    END Q[31]
  PIN Q[0]
    DIRECTION OUTPUT ;
    USE SIGNAL ;
    SHAPE ABUTMENT ;
    PORT
      LAYER M4 ;
      RECT 12.845 0.0 13.185 0.34 ;
      LAYER M3 ;
      RECT 12.845 0.0 13.185 0.2 ;
      LAYER M2 ;
      RECT 12.845 0.0 13.185 0.2 ;
      LAYER M1 ;
      RECT 12.845 0.0 13.185 0.2 ;
      END
    ANTENNADIFFAREA 0.1024 ;
    END Q[0]
  PIN VDDPE
    DIRECTION INOUT ;
    USE POWER ;
    PORT
      LAYER M4 ;
      RECT 0.0 5.59 586.59 6.01 ;
      END
    PORT
      LAYER M4 ;
      RECT 0.0 8.95 586.59 9.37 ;
      END
    PORT
      LAYER M4 ;
      RECT 0.0 12.78 586.59 13.28 ;
      END
    PORT
      LAYER M4 ;
      RECT 0.0 59.75 586.59 59.95 ;
      END
    PORT
      LAYER M4 ;
      RECT 0.0 62.63 586.59 62.85 ;
      END
    PORT
      LAYER M4 ;
      RECT 0.0 66.595 586.59 66.895 ;
      END
    PORT
      LAYER M4 ;
      RECT 0.0 68.755 586.59 68.975 ;
      END
    PORT
      LAYER M4 ;
      RECT 0.0 71.655 586.59 71.855 ;
      END
    PORT
      LAYER M4 ;
      RECT 0.0 110.81 586.59 111.11 ;
      END
    END VDDPE
  PIN VDDCE
    DIRECTION INOUT ;
    USE POWER ;
    PORT
      LAYER M4 ;
      RECT 0.0 4.19 586.59 4.61 ;
      END
    PORT
      LAYER M4 ;
      RECT 0.0 17.455 586.59 17.825 ;
      END
    PORT
      LAYER M4 ;
      RECT 0.0 61.83 586.59 62.03 ;
      END
    PORT
      LAYER M4 ;
      RECT 0.0 69.575 586.59 69.775 ;
      END
    PORT
      LAYER M4 ;
      RECT 0.0 110.01 586.59 110.21 ;
      END
    END VDDCE
  PIN VSSE
    DIRECTION INOUT ;
    USE GROUND ;
    PORT
      LAYER M4 ;
      RECT 0.0 1.15 586.59 1.45 ;
      END
    PORT
      LAYER M4 ;
      RECT 0.0 4.89 586.59 5.31 ;
      END
    PORT
      LAYER M4 ;
      RECT 0.0 8.25 586.59 8.67 ;
      END
    PORT
      LAYER M4 ;
      RECT 0.0 11.67 586.59 12.09 ;
      END
    PORT
      LAYER M4 ;
      RECT 0.0 56.895 586.59 57.095 ;
      END
    PORT
      LAYER M4 ;
      RECT 0.0 62.23 586.59 62.43 ;
      END
    PORT
      LAYER M4 ;
      RECT 0.0 67.695 586.59 67.895 ;
      END
    PORT
      LAYER M4 ;
      RECT 0.0 69.175 586.59 69.375 ;
      END
    PORT
      LAYER M4 ;
      RECT 0.0 74.51 586.59 74.71 ;
      END
    PORT
      LAYER M4 ;
      RECT 0.0 110.41 586.59 110.61 ;
      END
    END VSSE
  OBS
    #otc obstructions
    LAYER M1 DESIGNRULEWIDTH 0.1 ;
    RECT 573.845 0.0 586.59 0.3 ;
    RECT 569.015 0.0 573.305 0.3 ;
    RECT 557.045 0.0 568.475 0.3 ;
    RECT 552.215 0.0 556.505 0.3 ;
    RECT 540.245 0.0 551.675 0.3 ;
    RECT 535.415 0.0 539.705 0.3 ;
    RECT 523.445 0.0 534.875 0.3 ;
    RECT 518.615 0.0 522.905 0.3 ;
    RECT 506.645 0.0 518.075 0.3 ;
    RECT 501.815 0.0 506.105 0.3 ;
    RECT 489.845 0.0 501.275 0.3 ;
    RECT 485.015 0.0 489.305 0.3 ;
    RECT 473.045 0.0 484.475 0.3 ;
    RECT 468.215 0.0 472.505 0.3 ;
    RECT 456.245 0.0 467.675 0.3 ;
    RECT 451.995 0.0 455.705 0.3 ;
    RECT 439.445 0.0 450.875 0.3 ;
    RECT 434.615 0.0 438.905 0.3 ;
    RECT 422.645 0.0 434.075 0.3 ;
    RECT 417.815 0.0 422.105 0.3 ;
    RECT 405.845 0.0 417.275 0.3 ;
    RECT 401.015 0.0 405.305 0.3 ;
    RECT 389.045 0.0 400.475 0.3 ;
    RECT 384.215 0.0 388.505 0.3 ;
    RECT 372.245 0.0 383.675 0.3 ;
    RECT 367.415 0.0 371.705 0.3 ;
    RECT 355.445 0.0 366.875 0.3 ;
    RECT 350.615 0.0 354.905 0.3 ;
    RECT 338.645 0.0 350.075 0.3 ;
    RECT 333.815 0.0 338.105 0.3 ;
    RECT 321.845 0.0 333.275 0.3 ;
    RECT 317.595 0.0 321.305 0.3 ;
    RECT 315.53 0.0 316.475 0.3 ;
    RECT 314.52 0.0 314.99 0.3 ;
    RECT 313.465 0.0 313.98 0.3 ;
    RECT 312.66 0.0 312.925 0.3 ;
    RECT 308.575 0.0 312.12 0.3 ;
    RECT 293.185 0.0 308.035 0.3 ;
    RECT 291.785 0.0 292.065 0.3 ;
    RECT 291.11 0.0 291.245 0.3 ;
    RECT 290.385 0.0 290.57 0.3 ;
    RECT 288.56 0.0 289.845 0.3 ;
    RECT 285.31 0.0 288.02 0.3 ;
    RECT 283.89 0.0 284.77 0.3 ;
    RECT 282.06 0.0 283.35 0.3 ;
    RECT 280.64 0.0 281.52 0.3 ;
    RECT 278.81 0.0 280.1 0.3 ;
    RECT 277.39 0.0 278.27 0.3 ;
    RECT 275.56 0.0 276.85 0.3 ;
    RECT 270.115 0.0 275.02 0.3 ;
    RECT 265.285 0.0 269.575 0.3 ;
    RECT 253.315 0.0 264.745 0.3 ;
    RECT 248.485 0.0 252.775 0.3 ;
    RECT 236.515 0.0 247.945 0.3 ;
    RECT 231.685 0.0 235.975 0.3 ;
    RECT 219.715 0.0 231.145 0.3 ;
    RECT 214.885 0.0 219.175 0.3 ;
    RECT 202.915 0.0 214.345 0.3 ;
    RECT 198.085 0.0 202.375 0.3 ;
    RECT 186.115 0.0 197.545 0.3 ;
    RECT 181.285 0.0 185.575 0.3 ;
    RECT 169.315 0.0 180.745 0.3 ;
    RECT 164.485 0.0 168.775 0.3 ;
    RECT 152.515 0.0 163.945 0.3 ;
    RECT 147.685 0.0 151.395 0.3 ;
    RECT 135.715 0.0 147.145 0.3 ;
    RECT 130.885 0.0 135.175 0.3 ;
    RECT 118.915 0.0 130.345 0.3 ;
    RECT 114.085 0.0 118.375 0.3 ;
    RECT 102.115 0.0 113.545 0.3 ;
    RECT 97.285 0.0 101.575 0.3 ;
    RECT 85.315 0.0 96.745 0.3 ;
    RECT 80.485 0.0 84.775 0.3 ;
    RECT 68.515 0.0 79.945 0.3 ;
    RECT 63.685 0.0 67.975 0.3 ;
    RECT 51.715 0.0 63.145 0.3 ;
    RECT 46.885 0.0 51.175 0.3 ;
    RECT 34.915 0.0 46.345 0.3 ;
    RECT 30.085 0.0 34.375 0.3 ;
    RECT 18.115 0.0 29.545 0.3 ;
    RECT 13.285 0.0 16.995 0.3 ;
    RECT 0.0 0.0 12.745 0.3 ;
    RECT 0.0 0.3 586.59 111.35 ;
    LAYER VIA1 ;
    RECT 0.0 0.0 586.59 111.35 ;
    LAYER M2 DESIGNRULEWIDTH 0.1 ;
    RECT 573.845 0.0 586.59 0.3 ;
    RECT 569.015 0.0 573.305 0.3 ;
    RECT 557.045 0.0 568.475 0.3 ;
    RECT 552.215 0.0 556.505 0.3 ;
    RECT 540.245 0.0 551.675 0.3 ;
    RECT 535.415 0.0 539.705 0.3 ;
    RECT 523.445 0.0 534.875 0.3 ;
    RECT 518.615 0.0 522.905 0.3 ;
    RECT 506.645 0.0 518.075 0.3 ;
    RECT 501.815 0.0 506.105 0.3 ;
    RECT 489.845 0.0 501.275 0.3 ;
    RECT 485.015 0.0 489.305 0.3 ;
    RECT 473.045 0.0 484.475 0.3 ;
    RECT 468.215 0.0 472.505 0.3 ;
    RECT 456.245 0.0 467.675 0.3 ;
    RECT 451.995 0.0 455.705 0.3 ;
    RECT 439.445 0.0 450.875 0.3 ;
    RECT 434.615 0.0 438.905 0.3 ;
    RECT 422.645 0.0 434.075 0.3 ;
    RECT 417.815 0.0 422.105 0.3 ;
    RECT 405.845 0.0 417.275 0.3 ;
    RECT 401.015 0.0 405.305 0.3 ;
    RECT 389.045 0.0 400.475 0.3 ;
    RECT 384.215 0.0 388.505 0.3 ;
    RECT 372.245 0.0 383.675 0.3 ;
    RECT 367.415 0.0 371.705 0.3 ;
    RECT 355.445 0.0 366.875 0.3 ;
    RECT 350.615 0.0 354.905 0.3 ;
    RECT 338.645 0.0 350.075 0.3 ;
    RECT 333.815 0.0 338.105 0.3 ;
    RECT 321.845 0.0 333.275 0.3 ;
    RECT 317.595 0.0 321.305 0.3 ;
    RECT 315.53 0.0 316.475 0.3 ;
    RECT 314.52 0.0 314.99 0.3 ;
    RECT 313.465 0.0 313.98 0.3 ;
    RECT 312.66 0.0 312.925 0.3 ;
    RECT 308.575 0.0 312.12 0.3 ;
    RECT 293.185 0.0 308.035 0.3 ;
    RECT 291.785 0.0 292.065 0.3 ;
    RECT 291.11 0.0 291.245 0.3 ;
    RECT 290.385 0.0 290.57 0.3 ;
    RECT 288.56 0.0 289.845 0.3 ;
    RECT 285.31 0.0 288.02 0.3 ;
    RECT 283.89 0.0 284.77 0.3 ;
    RECT 282.06 0.0 283.35 0.3 ;
    RECT 280.64 0.0 281.52 0.3 ;
    RECT 278.81 0.0 280.1 0.3 ;
    RECT 277.39 0.0 278.27 0.3 ;
    RECT 275.56 0.0 276.85 0.3 ;
    RECT 270.115 0.0 275.02 0.3 ;
    RECT 265.285 0.0 269.575 0.3 ;
    RECT 253.315 0.0 264.745 0.3 ;
    RECT 248.485 0.0 252.775 0.3 ;
    RECT 236.515 0.0 247.945 0.3 ;
    RECT 231.685 0.0 235.975 0.3 ;
    RECT 219.715 0.0 231.145 0.3 ;
    RECT 214.885 0.0 219.175 0.3 ;
    RECT 202.915 0.0 214.345 0.3 ;
    RECT 198.085 0.0 202.375 0.3 ;
    RECT 186.115 0.0 197.545 0.3 ;
    RECT 181.285 0.0 185.575 0.3 ;
    RECT 169.315 0.0 180.745 0.3 ;
    RECT 164.485 0.0 168.775 0.3 ;
    RECT 152.515 0.0 163.945 0.3 ;
    RECT 147.685 0.0 151.395 0.3 ;
    RECT 135.715 0.0 147.145 0.3 ;
    RECT 130.885 0.0 135.175 0.3 ;
    RECT 118.915 0.0 130.345 0.3 ;
    RECT 114.085 0.0 118.375 0.3 ;
    RECT 102.115 0.0 113.545 0.3 ;
    RECT 97.285 0.0 101.575 0.3 ;
    RECT 85.315 0.0 96.745 0.3 ;
    RECT 80.485 0.0 84.775 0.3 ;
    RECT 68.515 0.0 79.945 0.3 ;
    RECT 63.685 0.0 67.975 0.3 ;
    RECT 51.715 0.0 63.145 0.3 ;
    RECT 46.885 0.0 51.175 0.3 ;
    RECT 34.915 0.0 46.345 0.3 ;
    RECT 30.085 0.0 34.375 0.3 ;
    RECT 18.115 0.0 29.545 0.3 ;
    RECT 13.285 0.0 16.995 0.3 ;
    RECT 0.0 0.0 12.745 0.3 ;
    RECT 0.0 0.3 586.59 111.35 ;
    LAYER VIA2 ;
    RECT 0.0 0.0 586.59 111.35 ;
    LAYER M3 DESIGNRULEWIDTH 0.1 ;
    RECT 573.845 0.0 586.59 0.3 ;
    RECT 569.015 0.0 573.305 0.3 ;
    RECT 557.045 0.0 568.475 0.3 ;
    RECT 552.215 0.0 556.505 0.3 ;
    RECT 540.245 0.0 551.675 0.3 ;
    RECT 535.415 0.0 539.705 0.3 ;
    RECT 523.445 0.0 534.875 0.3 ;
    RECT 518.615 0.0 522.905 0.3 ;
    RECT 506.645 0.0 518.075 0.3 ;
    RECT 501.815 0.0 506.105 0.3 ;
    RECT 489.845 0.0 501.275 0.3 ;
    RECT 485.015 0.0 489.305 0.3 ;
    RECT 473.045 0.0 484.475 0.3 ;
    RECT 468.215 0.0 472.505 0.3 ;
    RECT 456.245 0.0 467.675 0.3 ;
    RECT 451.995 0.0 455.705 0.3 ;
    RECT 439.445 0.0 450.875 0.3 ;
    RECT 434.615 0.0 438.905 0.3 ;
    RECT 422.645 0.0 434.075 0.3 ;
    RECT 417.815 0.0 422.105 0.3 ;
    RECT 405.845 0.0 417.275 0.3 ;
    RECT 401.015 0.0 405.305 0.3 ;
    RECT 389.045 0.0 400.475 0.3 ;
    RECT 384.215 0.0 388.505 0.3 ;
    RECT 372.245 0.0 383.675 0.3 ;
    RECT 367.415 0.0 371.705 0.3 ;
    RECT 355.445 0.0 366.875 0.3 ;
    RECT 350.615 0.0 354.905 0.3 ;
    RECT 338.645 0.0 350.075 0.3 ;
    RECT 333.815 0.0 338.105 0.3 ;
    RECT 321.845 0.0 333.275 0.3 ;
    RECT 317.595 0.0 321.305 0.3 ;
    RECT 315.53 0.0 316.475 0.3 ;
    RECT 314.52 0.0 314.99 0.3 ;
    RECT 313.465 0.0 313.98 0.3 ;
    RECT 312.66 0.0 312.925 0.3 ;
    RECT 308.575 0.0 312.12 0.3 ;
    RECT 293.185 0.0 308.035 0.3 ;
    RECT 291.785 0.0 292.065 0.3 ;
    RECT 291.11 0.0 291.245 0.3 ;
    RECT 290.385 0.0 290.57 0.3 ;
    RECT 288.56 0.0 289.845 0.3 ;
    RECT 285.31 0.0 288.02 0.3 ;
    RECT 283.89 0.0 284.77 0.3 ;
    RECT 282.06 0.0 283.35 0.3 ;
    RECT 280.64 0.0 281.52 0.3 ;
    RECT 278.81 0.0 280.1 0.3 ;
    RECT 277.39 0.0 278.27 0.3 ;
    RECT 275.56 0.0 276.85 0.3 ;
    RECT 270.115 0.0 275.02 0.3 ;
    RECT 265.285 0.0 269.575 0.3 ;
    RECT 253.315 0.0 264.745 0.3 ;
    RECT 248.485 0.0 252.775 0.3 ;
    RECT 236.515 0.0 247.945 0.3 ;
    RECT 231.685 0.0 235.975 0.3 ;
    RECT 219.715 0.0 231.145 0.3 ;
    RECT 214.885 0.0 219.175 0.3 ;
    RECT 202.915 0.0 214.345 0.3 ;
    RECT 198.085 0.0 202.375 0.3 ;
    RECT 186.115 0.0 197.545 0.3 ;
    RECT 181.285 0.0 185.575 0.3 ;
    RECT 169.315 0.0 180.745 0.3 ;
    RECT 164.485 0.0 168.775 0.3 ;
    RECT 152.515 0.0 163.945 0.3 ;
    RECT 147.685 0.0 151.395 0.3 ;
    RECT 135.715 0.0 147.145 0.3 ;
    RECT 130.885 0.0 135.175 0.3 ;
    RECT 118.915 0.0 130.345 0.3 ;
    RECT 114.085 0.0 118.375 0.3 ;
    RECT 102.115 0.0 113.545 0.3 ;
    RECT 97.285 0.0 101.575 0.3 ;
    RECT 85.315 0.0 96.745 0.3 ;
    RECT 80.485 0.0 84.775 0.3 ;
    RECT 68.515 0.0 79.945 0.3 ;
    RECT 63.685 0.0 67.975 0.3 ;
    RECT 51.715 0.0 63.145 0.3 ;
    RECT 46.885 0.0 51.175 0.3 ;
    RECT 34.915 0.0 46.345 0.3 ;
    RECT 30.085 0.0 34.375 0.3 ;
    RECT 18.115 0.0 29.545 0.3 ;
    RECT 13.285 0.0 16.995 0.3 ;
    RECT 0.0 0.0 12.745 0.3 ;
    RECT 0.0 0.3 586.59 111.35 ;
    LAYER VIA3 ;
    RECT 0.0 0.0 586.59 111.35 ;
    LAYER M4 DESIGNRULEWIDTH 0.1 ;
    RECT 573.845 0.0 586.59 0.44 ;
    RECT 569.015 0.0 573.305 0.44 ;
    RECT 557.045 0.0 568.475 0.44 ;
    RECT 552.215 0.0 556.505 0.44 ;
    RECT 540.245 0.0 551.675 0.44 ;
    RECT 535.415 0.0 539.705 0.44 ;
    RECT 523.445 0.0 534.875 0.44 ;
    RECT 518.615 0.0 522.905 0.44 ;
    RECT 506.645 0.0 518.075 0.44 ;
    RECT 501.815 0.0 506.105 0.44 ;
    RECT 489.845 0.0 501.275 0.44 ;
    RECT 485.015 0.0 489.305 0.44 ;
    RECT 473.045 0.0 484.475 0.44 ;
    RECT 468.215 0.0 472.505 0.44 ;
    RECT 456.245 0.0 467.675 0.44 ;
    RECT 451.995 0.0 455.705 0.44 ;
    RECT 439.445 0.0 450.875 0.44 ;
    RECT 434.615 0.0 438.905 0.44 ;
    RECT 422.645 0.0 434.075 0.44 ;
    RECT 417.815 0.0 422.105 0.44 ;
    RECT 405.845 0.0 417.275 0.44 ;
    RECT 401.015 0.0 405.305 0.44 ;
    RECT 389.045 0.0 400.475 0.44 ;
    RECT 384.215 0.0 388.505 0.44 ;
    RECT 372.245 0.0 383.675 0.44 ;
    RECT 367.415 0.0 371.705 0.44 ;
    RECT 355.445 0.0 366.875 0.44 ;
    RECT 350.615 0.0 354.905 0.44 ;
    RECT 338.645 0.0 350.075 0.44 ;
    RECT 333.815 0.0 338.105 0.44 ;
    RECT 321.845 0.0 333.275 0.44 ;
    RECT 317.595 0.0 321.305 0.44 ;
    RECT 315.53 0.0 316.475 0.44 ;
    RECT 314.52 0.0 314.99 0.44 ;
    RECT 313.465 0.0 313.98 0.44 ;
    RECT 312.66 0.0 312.925 0.44 ;
    RECT 308.575 0.0 312.12 0.44 ;
    RECT 293.185 0.0 308.035 0.44 ;
    RECT 291.785 0.0 292.065 0.44 ;
    RECT 291.11 0.0 291.245 0.44 ;
    RECT 290.385 0.0 290.57 0.44 ;
    RECT 288.56 0.0 289.845 0.44 ;
    RECT 285.31 0.0 288.02 0.44 ;
    RECT 283.89 0.0 284.77 0.44 ;
    RECT 282.06 0.0 283.35 0.44 ;
    RECT 280.64 0.0 281.52 0.44 ;
    RECT 278.81 0.0 280.1 0.44 ;
    RECT 277.39 0.0 278.27 0.44 ;
    RECT 275.56 0.0 276.85 0.44 ;
    RECT 270.115 0.0 275.02 0.44 ;
    RECT 265.285 0.0 269.575 0.44 ;
    RECT 253.315 0.0 264.745 0.44 ;
    RECT 248.485 0.0 252.775 0.44 ;
    RECT 236.515 0.0 247.945 0.44 ;
    RECT 231.685 0.0 235.975 0.44 ;
    RECT 219.715 0.0 231.145 0.44 ;
    RECT 214.885 0.0 219.175 0.44 ;
    RECT 202.915 0.0 214.345 0.44 ;
    RECT 198.085 0.0 202.375 0.44 ;
    RECT 186.115 0.0 197.545 0.44 ;
    RECT 181.285 0.0 185.575 0.44 ;
    RECT 169.315 0.0 180.745 0.44 ;
    RECT 164.485 0.0 168.775 0.44 ;
    RECT 152.515 0.0 163.945 0.44 ;
    RECT 147.685 0.0 151.395 0.44 ;
    RECT 135.715 0.0 147.145 0.44 ;
    RECT 130.885 0.0 135.175 0.44 ;
    RECT 118.915 0.0 130.345 0.44 ;
    RECT 114.085 0.0 118.375 0.44 ;
    RECT 102.115 0.0 113.545 0.44 ;
    RECT 97.285 0.0 101.575 0.44 ;
    RECT 85.315 0.0 96.745 0.44 ;
    RECT 80.485 0.0 84.775 0.44 ;
    RECT 68.515 0.0 79.945 0.44 ;
    RECT 63.685 0.0 67.975 0.44 ;
    RECT 51.715 0.0 63.145 0.44 ;
    RECT 46.885 0.0 51.175 0.44 ;
    RECT 34.915 0.0 46.345 0.44 ;
    RECT 30.085 0.0 34.375 0.44 ;
    RECT 18.115 0.0 29.545 0.44 ;
    RECT 13.285 0.0 16.995 0.44 ;
    RECT 0.0 0.0 12.745 0.44 ;
    RECT 0.0 0.44 586.59 1.15 ;
    RECT 0.0 1.45 586.59 4.19 ;
    RECT 0.0 4.61 586.59 4.89 ;
    RECT 0.0 5.31 586.59 5.59 ;
    RECT 0.0 6.01 586.59 8.25 ;
    RECT 0.0 8.67 586.59 8.95 ;
    RECT 0.0 9.37 586.59 11.67 ;
    RECT 0.0 12.09 586.59 12.78 ;
    RECT 0.0 13.28 586.59 17.455 ;
    RECT 0.0 17.825 586.59 56.895 ;
    RECT 0.0 57.095 586.59 59.75 ;
    RECT 0.0 59.95 586.59 61.83 ;
    RECT 0.0 62.03 586.59 62.23 ;
    RECT 0.0 62.43 586.59 62.63 ;
    RECT 0.0 62.85 586.59 66.595 ;
    RECT 0.0 66.895 586.59 67.695 ;
    RECT 0.0 67.895 586.59 68.755 ;
    RECT 0.0 68.975 586.59 69.175 ;
    RECT 0.0 69.375 586.59 69.575 ;
    RECT 0.0 69.775 586.59 71.655 ;
    RECT 0.0 71.855 586.59 74.51 ;
    RECT 0.0 74.71 586.59 110.01 ;
    RECT 0.0 110.21 586.59 110.41 ;
    RECT 0.0 110.61 586.59 110.81 ;
    RECT 0.0 111.11 586.59 111.35 ;
    END
  END picosoc_sram_2048x32

END LIBRARY

